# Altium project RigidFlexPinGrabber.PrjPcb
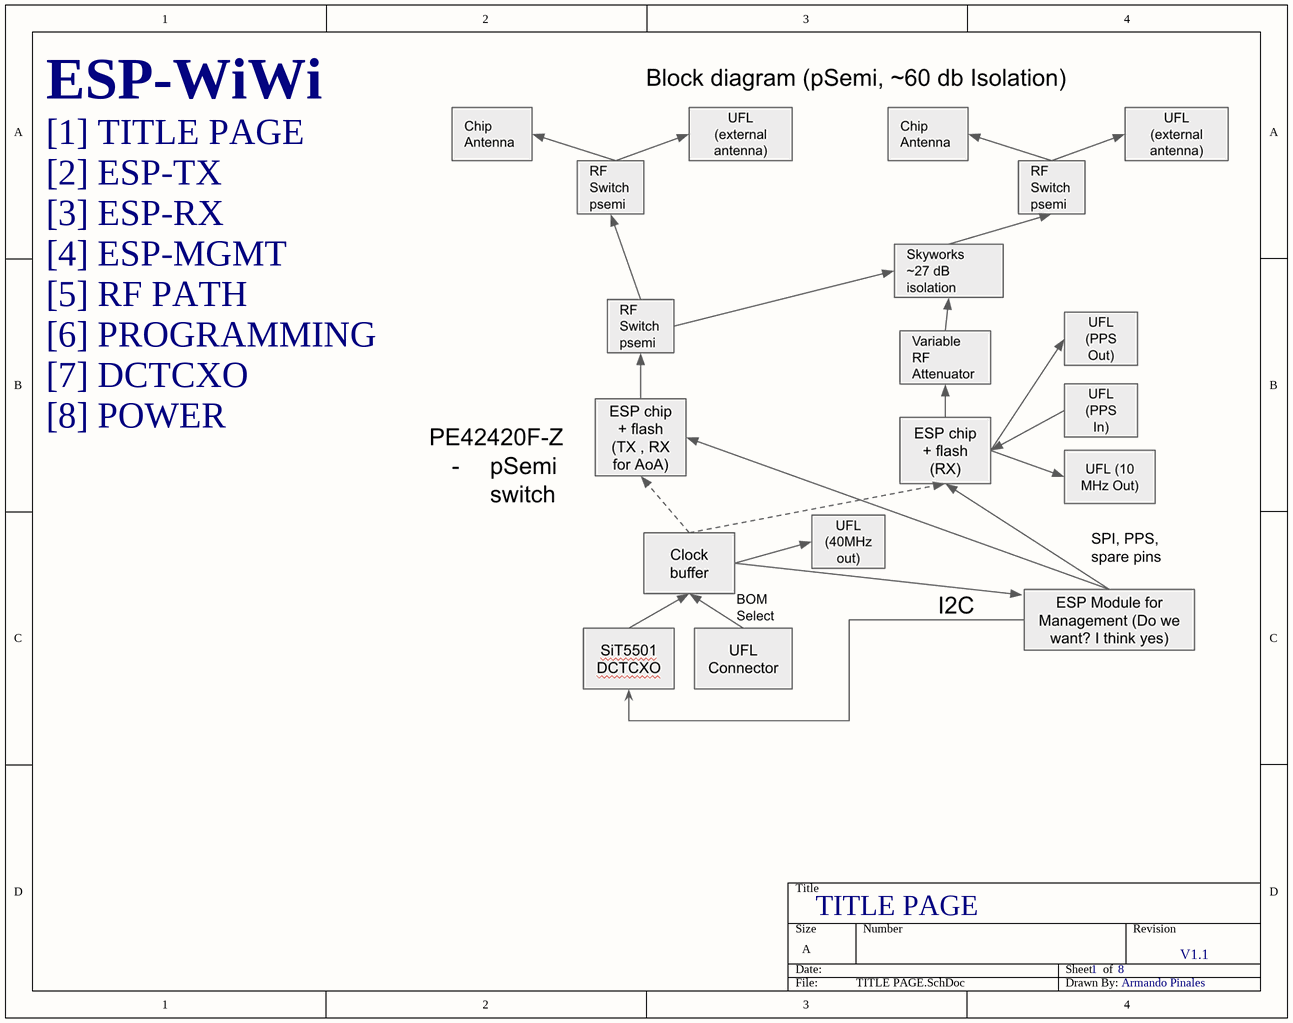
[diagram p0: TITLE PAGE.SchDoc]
DrawnBy: Armando Pinales; Revision: V1.1
1 sheet, 0 parts. Net scope: global (net labels, ports and power ports of the same name join across sheets).
Board file: pcb_v1.PcbDoc

## Sheet TITLE PAGE.SchDoc: TITLE PAGE
size A; SheetNumber: 1; SheetTotal: 8

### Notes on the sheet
- ESP-WiWi
- [1] TITLE PAGE
- [2] ESP-TX
- [3] ESP-RX
- [4] ESP-MGMT
- [5] RF PATH
- [6] PROGRAMMING
- [7] DCTCXO
- [8] POWER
